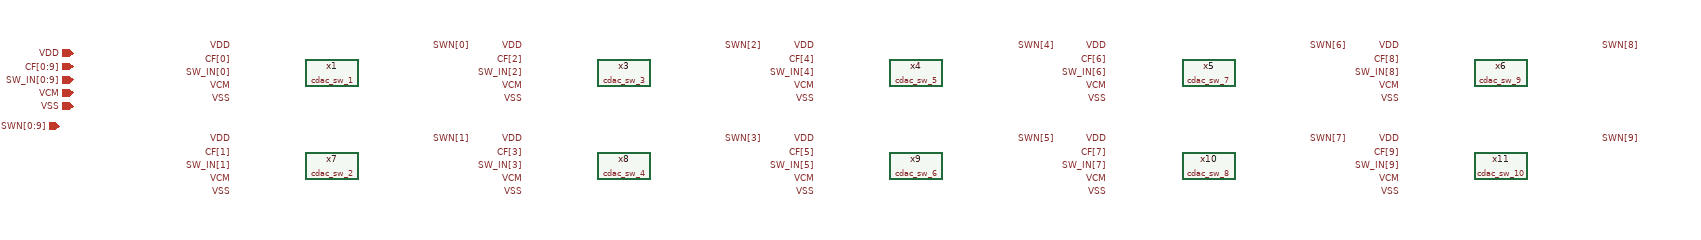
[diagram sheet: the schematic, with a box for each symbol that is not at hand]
v {xschem version=3.4.6 file_version=1.2}
G {}
K {}
V {}
S {}
E {}
C {devices/ipin.sym} 180 -580 0 0 {name=p18 lab=VDD}
C {devices/ipin.sym} 180 -560 0 0 {name=p19 lab=CF[0:9]}
C {devices/ipin.sym} 180 -540 0 0 {name=p20 lab=SW_IN[0:9]}
C {devices/ipin.sym} 180 -520 0 0 {name=p22 lab=VCM}
C {devices/ipin.sym} 180 -500 0 0 {name=p23 lab=VSS}
C {devices/iopin.sym} 160 -470 0 0 {name=p24 lab=SWN[0:9]}
C {cdac_sw_1.sym} 570 -550 0 0 {name=x1}
C {devices/lab_wire.sym} 420 -590 0 0 {name=p63 sig_type=std_logic lab=VDD}
C {devices/lab_wire.sym} 420 -510 0 0 {name=p65 sig_type=std_logic lab=VSS}
C {devices/lab_wire.sym} 720 -590 2 0 {name=p67 sig_type=std_logic lab=SWN[0]}
C {devices/lab_wire.sym} 420 -530 0 0 {name=p70 sig_type=std_logic lab=VCM}
C {devices/lab_wire.sym} 420 -570 0 0 {name=p71 sig_type=std_logic lab=CF[0]}
C {devices/lab_wire.sym} 420 -550 0 0 {name=p73 sig_type=std_logic lab=SW_IN[0]}
C {cdac_sw_3.sym} 1010 -550 0 0 {name=x3}
C {devices/lab_wire.sym} 860 -590 0 0 {name=p2 sig_type=std_logic lab=VDD}
C {devices/lab_wire.sym} 860 -510 0 0 {name=p3 sig_type=std_logic lab=VSS}
C {devices/lab_wire.sym} 1160 -590 2 0 {name=p4 sig_type=std_logic lab=SWN[2]}
C {devices/lab_wire.sym} 860 -530 0 0 {name=p5 sig_type=std_logic lab=VCM}
C {devices/lab_wire.sym} 860 -570 0 0 {name=p6 sig_type=std_logic lab=CF[2]}
C {devices/lab_wire.sym} 860 -550 0 0 {name=p7 sig_type=std_logic lab=SW_IN[2]}
C {cdac_sw_5.sym} 1450 -550 0 0 {name=x4}
C {devices/lab_wire.sym} 1300 -590 0 0 {name=p8 sig_type=std_logic lab=VDD}
C {devices/lab_wire.sym} 1300 -510 0 0 {name=p10 sig_type=std_logic lab=VSS}
C {devices/lab_wire.sym} 1600 -590 2 0 {name=p11 sig_type=std_logic lab=SWN[4]}
C {devices/lab_wire.sym} 1300 -530 0 0 {name=p12 sig_type=std_logic lab=VCM}
C {devices/lab_wire.sym} 1300 -570 0 0 {name=p13 sig_type=std_logic lab=CF[4]}
C {devices/lab_wire.sym} 1300 -550 0 0 {name=p14 sig_type=std_logic lab=SW_IN[4]}
C {cdac_sw_7.sym} 1890 -550 0 0 {name=x5}
C {devices/lab_wire.sym} 1740 -590 0 0 {name=p15 sig_type=std_logic lab=VDD}
C {devices/lab_wire.sym} 1740 -510 0 0 {name=p17 sig_type=std_logic lab=VSS}
C {devices/lab_wire.sym} 2040 -590 2 0 {name=p21 sig_type=std_logic lab=SWN[6]}
C {devices/lab_wire.sym} 1740 -530 0 0 {name=p25 sig_type=std_logic lab=VCM}
C {devices/lab_wire.sym} 1740 -570 0 0 {name=p26 sig_type=std_logic lab=CF[6]}
C {devices/lab_wire.sym} 1740 -550 0 0 {name=p27 sig_type=std_logic lab=SW_IN[6]}
C {cdac_sw_9.sym} 2330 -550 0 0 {name=x6}
C {devices/lab_wire.sym} 2180 -590 0 0 {name=p28 sig_type=std_logic lab=VDD}
C {devices/lab_wire.sym} 2180 -510 0 0 {name=p29 sig_type=std_logic lab=VSS}
C {devices/lab_wire.sym} 2480 -590 2 0 {name=p30 sig_type=std_logic lab=SWN[8]}
C {devices/lab_wire.sym} 2180 -530 0 0 {name=p31 sig_type=std_logic lab=VCM}
C {devices/lab_wire.sym} 2180 -570 0 0 {name=p32 sig_type=std_logic lab=CF[8]}
C {devices/lab_wire.sym} 2180 -550 0 0 {name=p33 sig_type=std_logic lab=SW_IN[8]}
C {cdac_sw_2.sym} 570 -410 0 0 {name=x7}
C {devices/lab_wire.sym} 420 -450 0 0 {name=p34 sig_type=std_logic lab=VDD}
C {devices/lab_wire.sym} 420 -370 0 0 {name=p35 sig_type=std_logic lab=VSS}
C {devices/lab_wire.sym} 720 -450 2 0 {name=p36 sig_type=std_logic lab=SWN[1]}
C {devices/lab_wire.sym} 420 -390 0 0 {name=p37 sig_type=std_logic lab=VCM}
C {devices/lab_wire.sym} 420 -430 0 0 {name=p38 sig_type=std_logic lab=CF[1]}
C {devices/lab_wire.sym} 420 -410 0 0 {name=p39 sig_type=std_logic lab=SW_IN[1]}
C {cdac_sw_4.sym} 1010 -410 0 0 {name=x8}
C {devices/lab_wire.sym} 860 -450 0 0 {name=p40 sig_type=std_logic lab=VDD}
C {devices/lab_wire.sym} 860 -370 0 0 {name=p41 sig_type=std_logic lab=VSS}
C {devices/lab_wire.sym} 1160 -450 2 0 {name=p42 sig_type=std_logic lab=SWN[3]}
C {devices/lab_wire.sym} 860 -390 0 0 {name=p43 sig_type=std_logic lab=VCM}
C {devices/lab_wire.sym} 860 -430 0 0 {name=p44 sig_type=std_logic lab=CF[3]}
C {devices/lab_wire.sym} 860 -410 0 0 {name=p45 sig_type=std_logic lab=SW_IN[3]}
C {cdac_sw_6.sym} 1450 -410 0 0 {name=x9}
C {devices/lab_wire.sym} 1300 -450 0 0 {name=p46 sig_type=std_logic lab=VDD}
C {devices/lab_wire.sym} 1300 -370 0 0 {name=p47 sig_type=std_logic lab=VSS}
C {devices/lab_wire.sym} 1600 -450 2 0 {name=p48 sig_type=std_logic lab=SWN[5]}
C {devices/lab_wire.sym} 1300 -390 0 0 {name=p49 sig_type=std_logic lab=VCM}
C {devices/lab_wire.sym} 1300 -430 0 0 {name=p50 sig_type=std_logic lab=CF[5]}
C {devices/lab_wire.sym} 1300 -410 0 0 {name=p51 sig_type=std_logic lab=SW_IN[5]}
C {cdac_sw_8.sym} 1890 -410 0 0 {name=x10}
C {devices/lab_wire.sym} 1740 -450 0 0 {name=p52 sig_type=std_logic lab=VDD}
C {devices/lab_wire.sym} 1740 -370 0 0 {name=p53 sig_type=std_logic lab=VSS}
C {devices/lab_wire.sym} 2040 -450 2 0 {name=p54 sig_type=std_logic lab=SWN[7]}
C {devices/lab_wire.sym} 1740 -390 0 0 {name=p55 sig_type=std_logic lab=VCM}
C {devices/lab_wire.sym} 1740 -430 0 0 {name=p56 sig_type=std_logic lab=CF[7]}
C {devices/lab_wire.sym} 1740 -410 0 0 {name=p57 sig_type=std_logic lab=SW_IN[7]}
C {cdac_sw_10.sym} 2330 -410 0 0 {name=x11}
C {devices/lab_wire.sym} 2180 -450 0 0 {name=p58 sig_type=std_logic lab=VDD}
C {devices/lab_wire.sym} 2180 -370 0 0 {name=p59 sig_type=std_logic lab=VSS}
C {devices/lab_wire.sym} 2480 -450 2 0 {name=p60 sig_type=std_logic lab=SWN[9]}
C {devices/lab_wire.sym} 2180 -390 0 0 {name=p61 sig_type=std_logic lab=VCM}
C {devices/lab_wire.sym} 2180 -430 0 0 {name=p62 sig_type=std_logic lab=CF[9]}
C {devices/lab_wire.sym} 2180 -410 0 0 {name=p64 sig_type=std_logic lab=SW_IN[9]}
